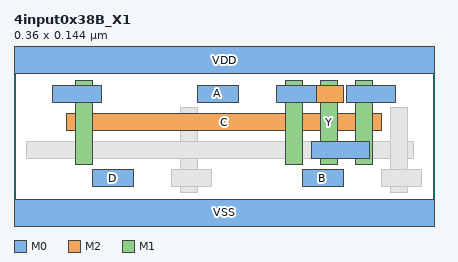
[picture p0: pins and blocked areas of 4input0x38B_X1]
MACRO 4input0x38B_X1
  CLASS CORE ;
  ORIGIN 0 0 ;
  FOREIGN 4input0x38B_X1 0 0 ;
  SIZE 0.3600 BY 0.1440 ;
  SYMMETRY X Y ;
  SITE coresite ;
  PIN A
    DIRECTION INPUT ;
    USE SIGNAL ;
    PORT
      LAYER M0 ;
        RECT 0.1575 0.1010 0.1920 0.1150 ;
    END
  END A
  PIN B
    DIRECTION INPUT ;
    USE SIGNAL ;
    PORT
      LAYER M0 ;
        RECT 0.2475 0.0290 0.2820 0.0430 ;
    END
  END B
  PIN C
    DIRECTION INPUT ;
    USE SIGNAL ;
    PORT
      LAYER M2 ;
        RECT 0.0450 0.0770 0.3150 0.0910 ;
      LAYER M1 ;
        RECT 0.0525 0.0480 0.0675 0.1200 ;
        RECT 0.2925 0.0480 0.3075 0.1200 ;
      LAYER M0 ;
        RECT 0.2850 0.1010 0.3270 0.1150 ;
        RECT 0.0330 0.1010 0.0750 0.1150 ;
    END
  END C
  PIN D
    DIRECTION INPUT ;
    USE SIGNAL ;
    PORT
      LAYER M0 ;
        RECT 0.0675 0.0290 0.1020 0.0430 ;
    END
  END D
  PIN Y
    DIRECTION OUTPUT ;
    USE SIGNAL ;
    PORT
      LAYER M2 ;
        RECT 0.2250 0.1010 0.2820 0.1150 ;
      LAYER M1 ;
        RECT 0.2325 0.0480 0.2475 0.1200 ;
        RECT 0.2625 0.0480 0.2775 0.1200 ;
      LAYER M0 ;
        RECT 0.2550 0.0530 0.3045 0.0670 ;
        RECT 0.2250 0.1010 0.2595 0.1150 ;
    END
  END Y
  PIN VDD
    DIRECTION INOUT ;
    USE POWER ;
    SHAPE ABUTMENT ;
    PORT
      LAYER M0 ;
        RECT 0.0000 0.1260 0.3600 0.1620 ;
    END
  END VDD
  PIN VSS
    DIRECTION INOUT ;
    USE GROUND ;
    SHAPE ABUTMENT ;
    PORT
      LAYER M0 ;
        RECT 0.0000 -0.0180 0.3600 0.0180 ;
    END
  END VSS
  OBS
    LAYER M2 ;
      RECT 0.1350 0.0530 0.3420 0.0670 ;
    LAYER V1 ;
      RECT 0.0530 0.0770 0.0670 0.0910 ;
      RECT 0.2930 0.0770 0.3070 0.0910 ;
      RECT 0.1430 0.0530 0.1570 0.0670 ;
      RECT 0.3230 0.0530 0.3370 0.0670 ;
      RECT 0.2330 0.1010 0.2470 0.1150 ;
      RECT 0.2630 0.1010 0.2770 0.1150 ;
    LAYER M1 ;
      RECT 0.1425 0.0240 0.1575 0.0960 ;
      RECT 0.3225 0.0240 0.3375 0.0960 ;
    LAYER V0 ;
      RECT 0.0530 0.1010 0.0670 0.1150 ;
      RECT 0.2930 0.1010 0.3070 0.1150 ;
      RECT 0.1430 0.0290 0.1570 0.0430 ;
      RECT 0.3230 0.0290 0.3370 0.0430 ;
      RECT 0.2330 0.1010 0.2470 0.1150 ;
      RECT 0.2630 0.0530 0.2770 0.0670 ;
    LAYER M0 ;
      RECT 0.1350 0.0290 0.1695 0.0430 ;
      RECT 0.3150 0.0290 0.3495 0.0430 ;
      RECT 0.0105 0.0530 0.2370 0.0670 ;
      RECT 0.0555 0.0770 0.1470 0.0910 ;
      RECT 0.1905 0.0770 0.3045 0.0910 ;
  END
END 4input0x38B_X1
